VERSION 5.7 ;
  NOWIREEXTENSIONATPIN ON ;
  DIVIDERCHAR "/" ;
  BUSBITCHARS "[]" ;
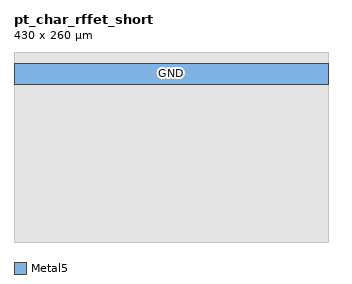
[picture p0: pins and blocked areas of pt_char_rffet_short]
MACRO pt_char_rffet_short
  CLASS BLOCK ;
  FOREIGN pt_char_rffet_short ;
  ORIGIN 215.000 130.000 ;
  SIZE 430.000 BY 260.000 ;
  PIN GND
    PORT
      LAYER Metal5 ;
        RECT -215.000 86.000 215.000 114.000 ;
    END
  END GND
  OBS
      LAYER Metal2 ;
        RECT -10.000 -2.000 -6.000 2.000 ;
      LAYER Metal3 ;
        RECT -10.000 -100.000 10.000 2.000 ;
      LAYER Metal4 ;
        RECT -170.000 -100.000 170.000 2.000 ;
      LAYER Metal5 ;
        RECT -215.000 114.600 215.000 130.000 ;
        RECT -215.000 85.400 -195.000 86.000 ;
        RECT -215.000 -130.000 215.000 85.400 ;
  END
END pt_char_rffet_short
END LIBRARY

